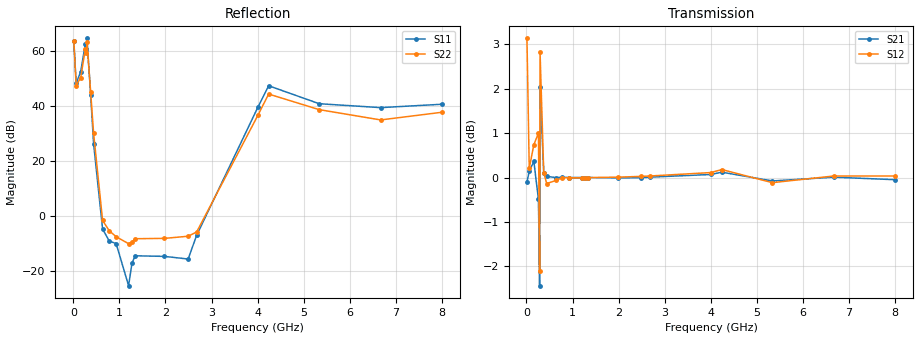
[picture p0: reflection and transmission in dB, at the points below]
!Agilent Technologies,N5230A,US43500312,A.07.50.67
!Agilent N5230A: A.07.50.67
!Date: Tuesday, June 09, 2015 15:33:11
!Correction: S11(Full 2 Port(1,2))
!S21(Full 2 Port(1,2))
!S12(Full 2 Port(1,2))
!S22(Full 2 Port(1,2))
!S2P File: Measurements: S11, S21, S12, S22:
# Hz S  MA  R 50
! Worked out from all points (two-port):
!   1601 points, 10 MHz to 8 GHz, reference 50 ohm
!   highest |S21| = 2.05 dB at 294.6 MHz (marker M1); lowest = -2.4 dB at 284.7 MHz (marker M2)
!   |S21| within 3 dB of the highest: 77.05 MHz to 172.6 MHz (95.51 MHz wide, 76.5 % of centre); 334.9 MHz to end of sweep (the widest 2 of 8)
!   lowest |S11| = -25.3 dB at 1.199 GHz (marker M3), VSWR 1.12, Z = 54.4 + j3.58 ohm
!   |S11| at or under -10 dB: 787.7 MHz to 928.8 MHz (141.1 MHz wide, 16.4 % of centre); 1.045 GHz to 2.087 GHz (1.041 GHz wide, 66.5 % of centre); 2.363 GHz to 2.614 GHz (250.1 MHz wide, 10.1 % of centre) (the widest 3 of 4)
!   |S22| runs from -13.9 to 63.6 dB; largest |S21 - S12| = 0.98
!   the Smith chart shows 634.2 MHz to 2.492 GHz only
!   S11 on the Smith chart (normalised r, x): 634.2 MHz: 0.38, +0.63; 779 MHz: 0.50, +0.17; 928.9 MHz: 0.90, -0.62; 1.273 GHz: 0.91, +0.26; 1.978 GHz: 0.71, +0.12; 2.492 GHz: 0.73, -0.11
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1e7  1499 171.1  0.9886 -8.5  1.435 -51.7  1520 -19.4
5.99375e7  257.8 325.7  1.016 -0.2  1.024 -4.0  233.1 92.2
1.598125e8  417 393.7  1.043 -1.8  1.089 -1.5  326.7 116.8
2.596875e8  1332 393.7  0.9447 -4.5  1.122 -9.5  1081 110.6
2.846562e8  1077 392.8  0.7553 -4.5  0.7841 -1.0  909.8 112.3
2.946438e8  1677 408.2  1.266 9.7  1.385 2.1  1448 129.1
3.745438e8  160.6 431.6  1.013 0.8  1.013 0.2  179.9 174.7
4.394625e8  20.37 410.0  1.003 0.1  0.9843 0.5  31.54 194.2
6.342188e8  0.5826 469.8  1 -0.0  0.9924 0.0  0.8324 373.2
7.790375e8  0.3518 514.5  1.001 0.0  0.9997 -0.2  0.5415 452.4
9.2885e8  0.3163 638.9  1 -0.0  0.9995 0.1  0.4214 576.7
1.198512e9  0.05454 756.9  1 0.0  0.9993 0.2  0.3156 686.6
1.273419e9  0.1413 822.5  0.9999 -0.0  1 0.1  0.3356 733.4
1.343331e9  0.1902 836.0  1 -0.0  0.9999 0.0  0.388 762.4
1.977538e9  0.1855 872.8  0.9991 0.0  1.001 0.0  0.3939 1028.1
2.491894e9  0.1661 926.9  0.9995 0.0  1.003 0.0  0.4307 1150.6
2.676662e9  0.4484 1014.1  1.001 0.0  1.004 0.0  0.5144 1231.3
4.005e9  93.93 1390.4  1.008 0.1  1.013 0.5  67.04 1520.0
4.239706e9  231.5 1343.0  1.014 -0.6  1.021 0.9  163.7 1462.1
5.338331e9  109.3 1318.9  0.9912 -0.1  0.9868 -0.1  85.33 1399.3
6.671662e9  92.84 1357.0  1.001 -0.2  1.004 0.1  55.5 1338.5
8e9  106.9 1385.8  0.9944 0.2  1.004 0.3  76.45 1306.9
